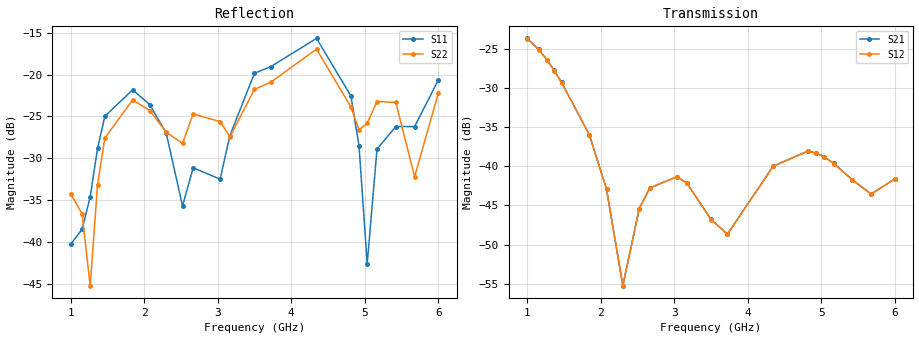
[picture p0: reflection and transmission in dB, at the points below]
!Agilent Technologies,E8364B,MY43040528,A.07.50.67
!Agilent E8364B: A.07.50.67
!Date: Sunday, March 01, 2026 21:18:12
!Correction: S11(Full 2 Port(1,2))
!S21(Full 2 Port(1,2))
!S12(Full 2 Port(1,2))
!S22(Full 2 Port(1,2))
!S2P File: Measurements: S11, S21, S12, S22:
# Hz S  dB  R 50
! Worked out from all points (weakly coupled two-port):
!   451 points, 1 GHz to 6 GHz, reference 50 ohm
!   highest |S21| = -23.64 dB at 1 GHz (marker M1); lowest = -55.3 dB at 2.3 GHz (marker M2)
!   lowest |S11| = -42.6 dB at 5.033 GHz (marker M3), VSWR 1.01, Z = 50.1 - j0.734 ohm
!   |S11| at or under -10 dB: start of sweep to end of sweep
!   |S22| runs from -45.2 to -16.6 dB; largest |S21 - S12| = 0.00024
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1e9  -40.31 83.5  -23.64 148.5  -23.68 148.5  -34.22 17.5
1.155556e9  -38.50 135.7  -25.06 58.5  -25.09 58.5  -36.63 19.1
1.266667e9  -34.63 167.5  -26.35 -5.5  -26.38 -5.5  -45.24 73.7
1.366667e9  -28.81 170.2  -27.74 -62.2  -27.77 -62.2  -33.17 107.6
1.466667e9  -24.97 153.6  -29.28 -117.7  -29.31 -117.7  -27.57 86.8
1.844444e9  -21.82 86.8  -35.95 37.5  -35.97 37.7  -23.03 -0.8
2.077778e9  -23.60 57.2  -42.90 -85.4  -42.95 -85.4  -24.30 -36.7
2.3e9  -26.98 32.5  -55.26 -132.5  -55.25 -132.3  -26.89 -60.4
2.522222e9  -35.71 50.9  -45.41 171.4  -45.45 171.4  -28.22 -49.6
2.666667e9  -31.15 82.6  -42.76 95.9  -42.79 95.9  -24.71 -56.4
3.033333e9  -32.50 80.4  -41.33 -102.5  -41.36 -102.5  -25.62 -113.7
3.166667e9  -27.29 104.6  -42.09 -174.5  -42.12 -174.5  -27.43 -105.0
3.5e9  -19.84 60.8  -46.79 22.5  -46.82 22.5  -21.77 -124.3
3.722222e9  -19.05 38.8  -48.67 -53.5  -48.69 -53.4  -20.91 -146.0
4.344444e9  -15.67 -40.7  -39.98 12.5  -40.02 12.5  -16.96 113.7
4.811111e9  -22.53 -121.1  -38.06 106.4  -38.09 106.4  -23.85 34.1
4.922222e9  -28.52 -137.9  -38.27 40.4  -38.31 40.5  -26.60 35.0
5.033333e9  -42.62 -82.6  -38.76 -26.1  -38.79 -26.1  -25.82 44.0
5.166667e9  -28.91 -33.5  -39.60 -107.1  -39.64 -107.0  -23.22 30.9
5.422222e9  -26.21 -68.4  -41.74 90.0  -41.78 90.1  -23.33 -23.9
5.677778e9  -26.22 -52.9  -43.53 -90.4  -43.57 -90.4  -32.21 -25.4
6e9  -20.65 -74.5  -41.59 41.2  -41.62 41.2  -22.25 -23.8
